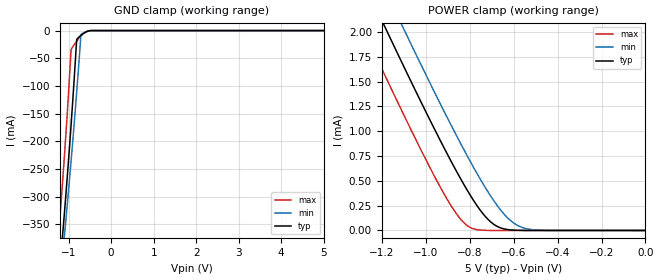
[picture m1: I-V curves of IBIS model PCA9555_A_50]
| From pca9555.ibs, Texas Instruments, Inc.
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[Model]   PCA9555_A_50
Model_type  Input
Vinl=1.35
Vinh=3.85
| variable   typ   min   max
C_comp   3.08pF   1.64pF   7.41pF
[Temperature Range]   40   100   -40
| Ambient temperature   25   85   -40
[Voltage range]   5   4.5   5.5
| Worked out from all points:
|   GND clamp passes 1 mA (typ) near -0.54 V on its own axis
|   POWER clamp passes 1 mA (typ) near -0.96 V on its own axis
[GND Clamp]
| PCA9555_A_50
|   Voltage   I(typ)   I(min)   I(max)
-5.5V     -1.952A    -1.991A    -1.822A
-1.24V    -456.1mA   -482.2mA   -371.1mA
-1.205V   -425.8mA   -455.2mA   -337.1mA
-1.135V   -362.9mA   -399.8mA   -265.2mA
-1.1V     -330.1mA   -371.2mA   -227.1mA
-1.07V    -301.2mA   -346.3mA   -193.2mA
-1.005V   -236.2mA   -290.9mA   -115.2mA
-945mV    -172.6mA   -237.7mA   -36.94mA
-810mV    -16.02mA   -110.1mA   -19.15mA
-710mV    -8.623mA   -7.36mA    -9.218mA
-555mV    -1.256mA   -1.321mA   -672uA
5V        122pA      5.559uA    78.9pA
[POWER Clamp]
| PCA9555_A_50
|   Voltage   I(typ)   I(min)   I(max)
-5.5V     23.22mA    23.56mA    22.79mA
-1.315V   2.658mA    3.034mA    2.172mA
-1.25V    2.35mA     2.727mA    1.863mA
-1.195V   2.092mA    2.469mA    1.605mA
-1.095V   1.628mA    2.005mA    1.141mA
-935mV    911uA      1.281mA    441.2uA
-835mV    496.2uA    849.9uA    97.5uA
-785mV    311.2uA    645.8uA    18.53uA
-715mV    108uA      382.7uA    733.7nA
-610mV    5.103uA    92.47uA    4.595nA
-490mV    68.92nA    4.139uA    120pA
-95.1fV   122pA      284.2pA    92.47pA
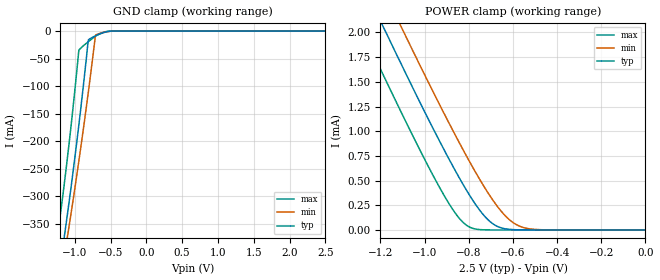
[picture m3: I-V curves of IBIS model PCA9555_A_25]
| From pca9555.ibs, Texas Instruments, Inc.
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[Model]   PCA9555_A_25
Model_type  Input
Vinl=0.69
Vinh=1.89
| variable   typ   min   max
C_comp   1.93pF   1.64pF   3.08pF
[Temperature Range]   40   100   -40
| Ambient temperature   25   85   -40
[Voltage range]   2.5   2.3   2.7
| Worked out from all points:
|   GND clamp passes 1 mA (typ) near -0.55 V on its own axis
|   POWER clamp passes 1 mA (typ) near -0.96 V on its own axis
[GND Clamp]
| PCA9555_A_25
|   Voltage   I(typ)   I(min)   I(max)
-5.5V     -1.952A    -1.991A    -1.822A
-1.245V   -460.3mA   -486mA     -375.9mA
-1.21V    -430.2mA   -459.1mA   -342.1mA
-1.14V    -367.5mA   -403.8mA   -270.6mA
-1.105V   -334.8mA   -375.4mA   -232.7mA
-1.085V   -315.7mA   -358.8mA   -210.3mA
-1.02V    -251.5mA   -303.9mA   -133.8mA
-945mV    -172.6mA   -237.7mA   -36.94mA
-810mV    -16.02mA   -110.1mA   -19.15mA
-710mV    -8.623mA   -7.36mA    -9.218mA
-505mV    -240uA     -374.5uA   -17.49uA
2.5V      65.27pA    853.9pA    39.07pA
[POWER Clamp]
| PCA9555_A_25
|   Voltage   I(typ)   I(min)   I(max)
-5.5V     23.22mA    23.56mA    22.79mA
-1.315V   2.658mA    3.034mA    2.172mA
-1.25V    2.35mA     2.727mA    1.863mA
-1.195V   2.092mA    2.469mA    1.605mA
-1.095V   1.628mA    2.005mA    1.141mA
-935mV    911uA      1.281mA    441.2uA
-835mV    496.2uA    849.9uA    97.5uA
-785mV    311.2uA    645.8uA    18.53uA
-715mV    108uA      382.7uA    733.7nA
-610mV    5.103uA    92.47uA    4.544nA
-490mV    68.86nA    4.139uA    69.34pA
-95.1fV   65.27pA    211.5pA    44.72pA
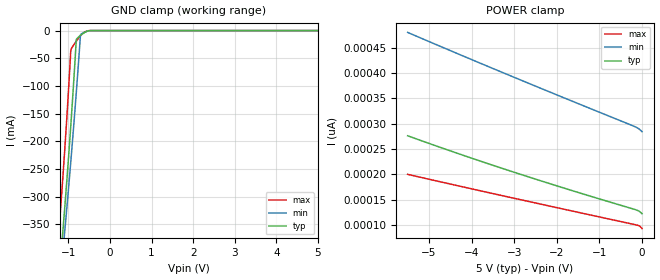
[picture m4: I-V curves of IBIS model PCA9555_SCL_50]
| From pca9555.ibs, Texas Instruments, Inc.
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[Model]   PCA9555_SCL_50
Model_type  Input
Vinl=1.35
Vinh=3.85
| variable   typ   min   max
C_comp   2.89pF   1.56pF   7.17pF
[Temperature Range]   40   100   -40
| Ambient temperature   25   85   -40
[Voltage range]   5   4.5   5.5
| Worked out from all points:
|   GND clamp passes 1 mA (typ) near -0.54 V on its own axis
[GND Clamp]
| PCA9555_SCL_50
|   Voltage   I(typ)   I(min)   I(max)
-5.5V     -1.952A    -1.991A    -1.822A
-1.24V    -456.1mA   -482.2mA   -371.1mA
-1.205V   -425.8mA   -455.2mA   -337.1mA
-1.135V   -362.9mA   -399.8mA   -265.2mA
-1.1V     -330.1mA   -371.2mA   -227.1mA
-1.07V    -301.2mA   -346.3mA   -193.2mA
-1.005V   -236.2mA   -290.9mA   -115.2mA
-945mV    -172.6mA   -237.7mA   -36.94mA
-810mV    -16.02mA   -110.1mA   -19.15mA
-710mV    -8.623mA   -7.36mA    -9.218mA
-555mV    -1.256mA   -1.321mA   -672uA
5V        122pA      305.6pA    79.4pA
[POWER Clamp]
| PCA9555_SCL_50
|   Voltage   I(typ)   I(min)   I(max)
-5.5V     276.1pA    480.5pA    199.8pA
-4.285V   240.1pA    436.9pA    176.6pA
-3.025V   204.6pA    392.5pA    153pA
-1.71V    169.5pA    347pA      128.7pA
-140mV    129.6pA    293pA      99.92pA
-55mV     126.1pA    288.5pA    97.4pA
-95.1fV   122pA      284.2pA    92.47pA
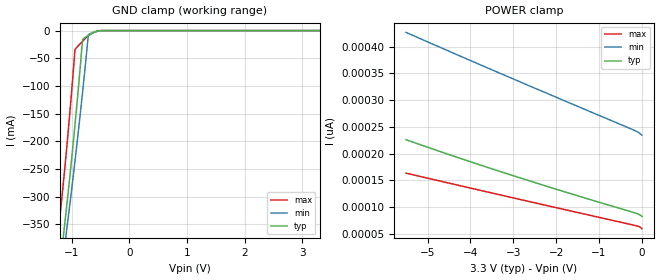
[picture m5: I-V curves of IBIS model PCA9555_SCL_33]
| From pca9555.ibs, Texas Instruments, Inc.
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[Model]   PCA9555_SCL_33
Model_type  Input
Vinl=0.9
Vinh=2.52
| variable   typ   min   max
C_comp   2.12pF   1.54pF   4.92pF
[Temperature Range]   40   100   -40
| Ambient temperature   25   85   -40
[Voltage range]   3.3   3   3.6
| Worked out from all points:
|   GND clamp passes 1 mA (typ) near -0.54 V on its own axis
[GND Clamp]
| PCA9555_SCL_33
|   Voltage   I(typ)   I(min)   I(max)
-5.5V     -1.952A    -1.991A    -1.822A
-1.24V    -456.1mA   -482.2mA   -371.1mA
-1.205V   -425.8mA   -455.2mA   -337.1mA
-1.135V   -362.9mA   -399.8mA   -265.2mA
-1.1V     -330.1mA   -371.2mA   -227.1mA
-1.07V    -301.2mA   -346.3mA   -193.2mA
-1.005V   -236.2mA   -290.9mA   -115.2mA
-945mV    -172.6mA   -237.7mA   -36.94mA
-810mV    -16.02mA   -110.1mA   -19.15mA
-710mV    -8.623mA   -7.36mA    -9.218mA
-505mV    -240uA     -374.5uA   -17.49uA
3.3V      82.96pA    248pA      52.06pA
[POWER Clamp]
| PCA9555_SCL_33
|   Voltage   I(typ)   I(min)   I(max)
-5.5V     226.2pA    426.8pA    163.7pA
-4.255V   191.9pA    383.1pA    140.6pA
-2.945V   157.5pA    337.9pA    116.5pA
-1.625V   124.5pA    292.8pA    92.42pA
-145mV    89pA       242.5pA    65.66pA
-55mV     85.99pA    238.2pA    63.4pA
-95.1fV   82.96pA    234.7pA    59.99pA
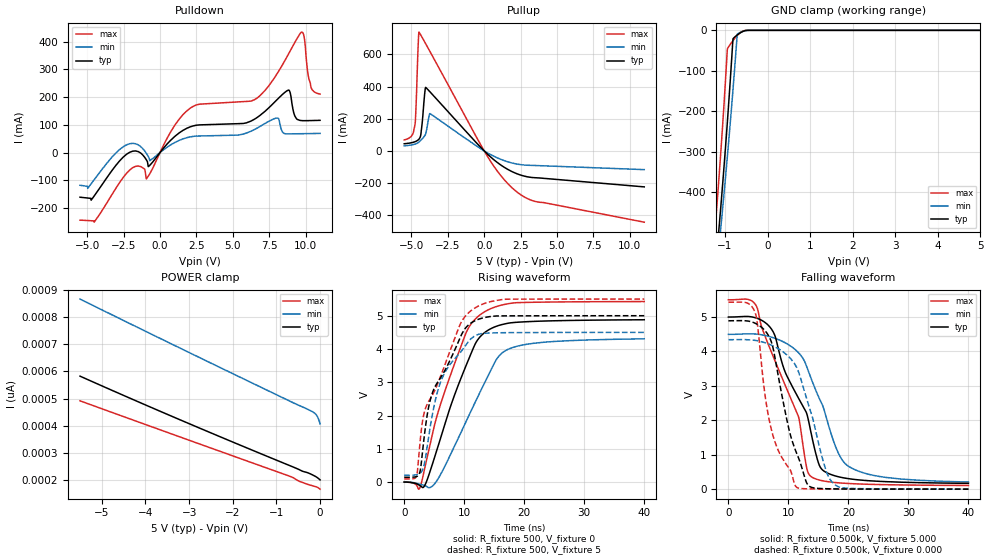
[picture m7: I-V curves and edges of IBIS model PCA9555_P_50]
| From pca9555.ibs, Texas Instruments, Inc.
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[Model]   PCA9555_P_50
Model_type  I/O
Vinl=1.35
Vinh=3.85
Enable   Active-Low
Vref =   5V
Rref =   1k
Cref =   50p
Vmeas =   2.5
| variable   typ   min   max
C_comp   5.26pF   3.57pF   9.96pF
| C_pullup   10.27pF   5.19pF   16.78pF
| C_pulldown   3.97pF   3.22pF   5.97pF
| C_tri-state   5.26pF   3.57pF   9.96pF
[Temperature Range]   40   100   -40
| Ambient temperature   25   85   -40
[Voltage range]   5   4.5   5.5
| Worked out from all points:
|   slope of the pulldown table from 0 to 0.75 V, typ, clamps not added: 16.6 ohm
|   slope of the pullup table from 0 to 0.75 V, typ, clamps not added: 12.2 ohm
|   GND clamp passes 1 mA (typ) near -0.53 V on its own axis
|   rising waveform, R_fixture 500, V_fixture 0: 20-80 % time 5.77ns typ, 6.85ns min, 5.74ns max; typ from 0 V to 4.88 V
|   falling waveform, R_fixture 0.500k, V_fixture 5.000: 20-80 % time 6.04ns typ, 5.41ns min, 6.35ns max; typ from 5 V to 0.169 V
|   rising waveform, R_fixture 500, V_fixture 5: 20-80 % time 5.39ns typ, 4.29ns min, 5.99ns max; typ from 0.145 V to 5 V
|   falling waveform, R_fixture 0.500k, V_fixture 0.000: 20-80 % time 3.86ns typ, 4.17ns min, 3.3ns max; typ from 4.89 V to 0.001 V
[GND Clamp]
| PCA9555_P_50
|   Voltage   I(typ)   I(min)   I(max)
-5.5V     -2.659A    -2.671A    -2.55A
-1.25V    -620.9mA   -649.9mA   -515.2mA
-1.215V   -580.7mA   -614.3mA   -469.4mA
-1.14V    -490.9mA   -535.7mA   -365.6mA
-1.105V   -447.3mA   -497.9mA   -314.2mA
-1.085V   -421.8mA   -476mA     -283.9mA
-1.02V    -335.9mA   -403.1mA   -180.3mA
-945mV    -230.4mA   -315.4mA   -49.25mA
-810mV    -21.17mA   -146.1mA   -25.59mA
-710mV    -11.45mA   -9.703mA   -12.46mA
-575mV    -2.573mA   -2.443mA   -1.831mA
5V        200.9pA    476.3pA    136.3pA
[POWER Clamp]
| PCA9555_P_50
|   Voltage   I(typ)   I(min)   I(max)
-5.5V     582.7pA    866.5pA    491.9pA
-3.195V   421.2pA    684.9pA    358.1pA
-720mV    255.2pA    492.9pA    215.8pA
-620mV    248.5pA    485.2pA    209.3pA
-460mV    237.2pA    473.5pA    194.6pA
-205mV    221.8pA    454.4pA    180.7pA
-125mV    215.3pA    446.6pA    177.1pA
-80mV     211.1pA    439pA      174.8pA
-40mV     206.5pA    426.4pA    171.8pA
-95.1fV   200.9pA    407pA      166.8pA
[Pulldown]
| PCA9555_P_50
|   Voltage   I(typ)   I(min)   I(max)
-5.5V     -161.3mA   -118.2mA   -244mA
-4.53V    -157.1mA   -98.37mA   -251.4mA
-2.09V    700uA      31.71mA    -63.39mA
-810mV    -51.16mA   -14.18mA   -85.28mA
1.86V     87.86mA    53.74mA    151.1mA
6.5V      120.4mA    83.16mA    190.6mA
8.07V     192mA      124.3mA    286.3mA
8.805V    224.8mA    67.3mA     353mA
9.715V    115.2mA    67.82mA    434.4mA
9.91V     114.8mA    67.97mA    415.8mA
10.38V    115.3mA    68.36mA    235.3mA
11V       116.1mA    68.89mA    210.6mA
[Pullup]
| PCA9555_P_50
|   Voltage   I(typ)   I(min)   I(max)
-5.5V     44.69mA    31.56mA    68.44mA
-4.965V   51.88mA    38.04mA    96.98mA
-4.755V   57.61mA    42.62mA    167.1mA
-4.54V    68.59mA    51.23mA    659.1mA
-4.485V   73.46mA    55.14mA    739.4mA
-4.345V   110mA      67.68mA    718.2mA
-4.025V   395.4mA    106.6mA    666.9mA
-3.74V    368.8mA    232.6mA    620.1mA
215mV     -18.98mA   -11.6mA    -32.74mA
2.1V      -136.4mA   -78.84mA   -244.4mA
3.52V     -166.7mA   -90.61mA   -314.5mA
11V       -223.6mA   -116.2mA   -443.2mA
[Ramp]
| PCA9555_P_50
| variable   typ   min   max
dV/dt_r   3.02/5.92E-09   2.68/7.11E-09   3.38/5.86E-09
dV/dt_f   2.91/6.05E-09   2.55/5.43E-09   3.25/6.38E-09
R_load = 500
[Rising Waveform]
| PCA9555_P_50
R_fixture =   500
C_fixture =   0
L_fixture =   0
V_fixture =   0
V_fixture_min = 0
V_fixture_max = 0
|   Time   V(typ)   V(min)   V(max)
0s        1.669nV    3.101nV    1.088nV
2.47ns    -88.81mV   -56.47mV   -210.5mV
3.46ns    -87.73mV   -106.1mV   451.7mV
5.215ns   833.5mV    -17.69mV   1.827V
8.355ns   2.599V     1.072V     3.54V
10.56ns   3.611V     1.916V     4.582V
12.66ns   4.37V      2.713V     5.03V
15.57ns   4.696V     3.739V     5.287V
18.15ns   4.793V     4.048V     5.383V
40ns      4.878V     4.305V     5.425V
[Falling Waveform]
R_fixture = 0.500k
V_fixture = 5.000
V_fixture_min = 4.500
V_fixture_max = 5.500
C_fixture = 0.000
L_fixture = 0.000
|  time   V(typ)   V(min)   V(max)
0s        5V         4.497V     5.5V
4.705ns   4.967V     4.504V     5.302V
7.59ns    4.526V     4.392V     3.802V
11.66ns   2.651V     3.968V     2.117V
13.05ns   2.2V       3.563V     620.6mV
13.76ns   1.649V     3.227V     368.6mV
15.48ns   594.7mV    2.51V      252.3mV
18.09ns   372mV      1.142V     188.7mV
20ns      305.8mV    666.4mV    165.4mV
40ns      169.2mV    207.1mV    107.2mV
[Rising Waveform]
| PCA9555_P_50
R_fixture =   500
C_fixture =   0
L_fixture =   0
V_fixture =   5
V_fixture_min = 4.5
V_fixture_max = 5.5
|   Time   V(typ)   V(min)   V(max)
0s        144.8mV    205.4mV    95.96mV
2.03ns    164.3mV    220.3mV    173.6mV
2.625ns   311.1mV    261.1mV    1.166V
2.99ns    811.4mV    346.6mV    1.759V
4.265ns   2.412V     1.58V      2.48V
6.06ns    3.135V     3.004V     3.181V
9.305ns   4.331V     3.887V     4.733V
11.22ns   4.792V     4.324V     5.163V
16.86ns   4.995V     4.489V     5.494V
40ns      4.999V     4.499V     5.5V
[Falling Waveform]
R_fixture = 0.500k
V_fixture = 0.000
V_fixture_min = 0.000
V_fixture_max = 0.000
C_fixture = 0.000
L_fixture = 0.000
|  time   V(typ)   V(min)   V(max)
0s        4.891V     4.341V     5.43V
4.465ns   4.819V     4.321V     5.123V
6.82ns    4.415V     4.208V     1.994V
8.15ns    3.442V     4.097V     1.19V
10.05ns   1.768V     3.847V     623.5mV
11.37ns   1.046V     3.538V     55.39mV
13.39ns   98.39mV    2.429V     9.881mV
16.28ns   13.79mV    535.9mV    4.686mV
17.83ns   8.967mV    118.8mV    3.599mV
40ns      957uV      1.856mV    497.1uV
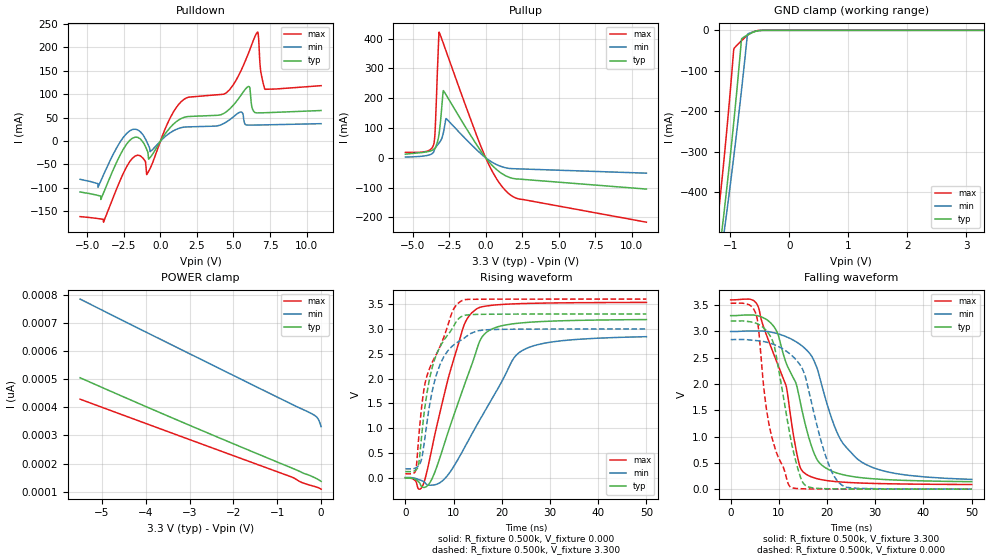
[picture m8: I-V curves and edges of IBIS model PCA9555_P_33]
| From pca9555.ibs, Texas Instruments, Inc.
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[Model]   PCA9555_P_33
Model_type  I/O
Vinl=0.9
Vinh=2.52
Enable   Active-Low
Vref =   3.3V
Rref =   1k
Cref =   50p
Vmeas =   1.65
| variable   typ   min   max
C_comp   4.36pF   3.54pF   7.68pF
| C_pullup   8.79pF   4.63pF   15.14pF
| C_pulldown   3.18pF   2.12pF   3.93pF
| C_tri-state   4.36pF   3.54pF   7.68pF
[Temperature Range]   40   100   -40
| Ambient temperature   25   85   -40
[Voltage range]   3.3   3   3.6
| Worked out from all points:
|   slope of the pulldown table from 0 to 0.495 V, typ, clamps not added: 21.7 ohm
|   slope of the pullup table from 0 to 0.495 V, typ, clamps not added: 17.6 ohm
|   GND clamp passes 1 mA (typ) near -0.53 V on its own axis
|   rising waveform, R_fixture 0.500k, V_fixture 0.000: 20-80 % time 6.77ns typ, 9.64ns min, 5.63ns max; typ from 0 V to 3.19 V
|   falling waveform, R_fixture 0.500k, V_fixture 3.300: 20-80 % time 6.32ns typ, 7.15ns min, 5.91ns max; typ from 3.3 V to 0.142 V
|   rising waveform, R_fixture 0.500k, V_fixture 3.300: 20-80 % time 4.04ns typ, 4ns min, 5.46ns max; typ from 0.127 V to 3.3 V
|   falling waveform, R_fixture 0.500k, V_fixture 0.000: 20-80 % time 3.8ns typ, 5ns min, 3.45ns max; typ from 3.2 V to 0 V
[GND Clamp]
| PCA9555_P_33
|   Voltage   I(typ)   I(min)   I(max)
-5.5V     -2.659A    -2.671A    -2.55A
-1.25V    -620.9mA   -649.9mA   -515.2mA
-1.215V   -580.7mA   -614.3mA   -469.4mA
-1.14V    -490.9mA   -535.7mA   -365.6mA
-1.105V   -447.3mA   -497.9mA   -314.2mA
-1.085V   -421.8mA   -476mA     -283.9mA
-1.02V    -335.9mA   -403.1mA   -180.3mA
-945mV    -230.4mA   -315.4mA   -49.25mA
-810mV    -21.17mA   -146.1mA   -25.59mA
-710mV    -11.45mA   -9.703mA   -12.46mA
-460mV    -14.25uA   -32.32uA   -4.731uA
3.3V      136.5pA    383.9pA    92.9pA
[POWER Clamp]
| PCA9555_P_33
|   Voltage   I(typ)   I(min)   I(max)
-5.5V     505.4pA    785.5pA    429pA
-3.22V    350.6pA    607.7pA    297.7pA
-715mV    186.9pA    414.5pA    154.3pA
-620mV    180.8pA    407.2pA    148.2pA
-450mV    169pA      394.8pA    133.1pA
-210mV    154pA      376.8pA    120.9pA
-130mV    148pA      369.3pA    117.3pA
-80mV     144.1pA    361.4pA    114.9pA
-40mV     140.5pA    349.5pA    112.3pA
-95.1fV   136.5pA    331.1pA    108.6pA
[Pulldown]
| PCA9555_P_33
|   Voltage   I(typ)   I(min)   I(max)
-5.5V     -108.8mA   -81.65mA   -161.4mA
-3.9V     -111.1mA   -72.36mA   -173.3mA
-1.91V    6.229mA    24.76mA    -36.43mA
-1.2V     -1.926mA   13.5mA     -36.3mA
-940mV    -17.78mA   -841.7uA   -71.68mA
1.26V     45.29mA    27.14mA    78.76mA
4.51V     62.52mA    40.64mA    103mA
6.02V     116.6mA    34.12mA    187.2mA
6.64V     60.2mA     34.28mA    232.8mA
6.855V    60.3mA     34.41mA    151.8mA
7.155V    60.56mA    34.61mA    110.6mA
11V       65.25mA    37.16mA    118.3mA
[Pullup]
| PCA9555_P_33
|   Voltage   I(typ)   I(min)   I(max)
-5.5V     12.07mA    2.44mA     18.27mA
-4.035V   20.06mA    7.564mA    21.8mA
-3.555V   28.68mA    20.6mA     45.81mA
-3.465V   33.35mA    31.5mA     89.22mA
-3.19V    81.65mA    50.02mA    421.9mA
-2.9V     225.5mA    83.94mA    383.7mA
-2.71V    211mA      131.6mA    357.5mA
-95mV     6.141mA    3.694mA    10.69mA
700mV     -37.53mA   -21.75mA   -66.95mA
1.495V    -63.29mA   -34.72mA   -116.7mA
2.27V     -71.32mA   -37.15mA   -138.1mA
11V       -105mA     -51.54mA   -216.1mA
[Ramp]
| PCA9555_P_33
| variable   typ   min   max
dV/dt_r   2.03/7.15E-09   1.78/1.02E-08   2.26/5.89E-09
dV/dt_f   1.90/6.33E-09   1.67/7.17E-09   2.12/5.96E-09
R_load = 500
[Rising Waveform]
R_fixture = 0.500k
V_fixture = 0.000
V_fixture_min = 0.000
V_fixture_max = 0.000
C_fixture = 0.000
L_fixture = 0.000
|  time   V(typ)   V(min)   V(max)
0s        1.457nV    9.486mV    934.2pV
3.68ns    -189.5mV   -67.33mV   -137.7mV
5.33ns    -55.59mV   -147.1mV   509.8mV
7.465ns   496.6mV    -76.36mV   1.436V
11.7ns    1.719V     508.3mV    2.932V
14.58ns   2.513V     1.021V     3.388V
17.26ns   2.961V     1.474V     3.466V
22.33ns   3.102V     2.387V     3.502V
24.55ns   3.124V     2.58V      3.51V
50ns      3.187V     2.843V     3.533V
[Falling Waveform]
R_fixture = 0.500k
V_fixture = 3.300
V_fixture_min = 3.000
V_fixture_max = 3.600
C_fixture = 0.000
L_fixture = 0.000
|  time   V(typ)   V(min)   V(max)
0s        3.3V       2.998V     3.6V
5.685ns   3.296V     3.007V     3.477V
9.67ns    2.979V     2.958V     2.395V
11.52ns   2.397V     2.899V     1.958V
13.85ns   1.914V     2.787V     623.3mV
15.33ns   1.288V     2.683V     304.8mV
18.52ns   489.9mV    2.111V     186.6mV
22.28ns   300.3mV    1.037V     140.7mV
26.51ns   224.7mV    558.4mV    118.5mV
50ns      142.4mV    185.5mV    88.51mV
[Rising Waveform]
R_fixture = 0.500k
V_fixture = 3.300
V_fixture_min = 3.000
V_fixture_max = 3.600
C_fixture = 0.000
L_fixture = 0.000
|  time   V(typ)   V(min)   V(max)
0s        126.8mV    183.4mV    82.7mV
2.06ns    149.9mV    196.9mV    127mV
2.6ns     216.1mV    230.5mV    609.6mV
3.29ns    751.7mV    355.8mV    1.35V
3.915ns   1.322V     707.5mV    1.816V
5.67ns    2.258V     1.787V     2.345V
7.945ns   2.765V     2.431V     2.825V
11.1ns    3.209V     2.748V     3.528V
16.73ns   3.294V     2.981V     3.597V
50ns      3.3V       2.999V     3.6V
[Falling Waveform]
R_fixture = 0.500k
V_fixture = 0.000
V_fixture_min = 0.000
V_fixture_max = 0.000
C_fixture = 0.000
L_fixture = 0.000
|  time   V(typ)   V(min)   V(max)
0s        3.197V     2.844V     3.536V
5.26ns    3.156V     2.826V     3.325V
7.08ns    3.046V     2.803V     1.765V
8.02ns    2.939V     2.781V     1.203V
9.18ns    2.672V     2.743V     786.7mV
12.38ns   992.6mV    2.566V     44.12mV
15.3ns    88.47mV    2.194V     6.862mV
19.64ns   9.347mV    648.3mV    2.802mV
22.99ns   4.719mV    82.58mV    1.826mV
50ns      496uV      1.201mV    227.2uV
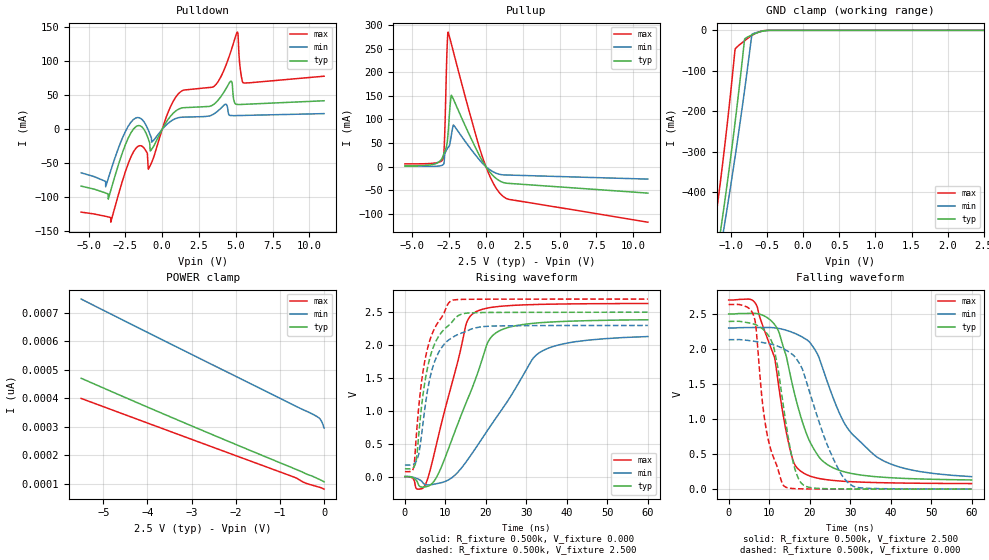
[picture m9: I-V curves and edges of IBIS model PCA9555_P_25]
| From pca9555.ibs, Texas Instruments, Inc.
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[Model]   PCA9555_P_25
Model_type  I/O
Vinl=0.69
Vinh=1.89
Enable   Active-Low
Vref =   2.5V
Rref =   1k
Cref =   50p
Vmeas =   1.25
| variable   typ   min   max
C_comp   3.89pF   3.28pF   5.37pF
| C_pullup   7.69pF   4.25pF   13.66pF
| C_pulldown   2.92pF   1.84pF   3.90pF
| C_tri-state   3.89pF   3.28pF   5.37pF
[Temperature Range]   40   100   -40
| Ambient temperature   25   85   -40
[Voltage range]   2.5   2.3   2.7
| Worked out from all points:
|   slope of the pulldown table from 0 to 0.375 V, typ, clamps not added: 27.3 ohm
|   slope of the pullup table from 0 to 0.375 V, typ, clamps not added: 24.6 ohm
|   GND clamp passes 1 mA (typ) near -0.53 V on its own axis
|   rising waveform, R_fixture 0.500k, V_fixture 0.000: 20-80 % time 8.64ns typ, 13.3ns min, 6.46ns max; typ from 0 V to 2.38 V
|   falling waveform, R_fixture 0.500k, V_fixture 2.500: 20-80 % time 7.2ns typ, 11.5ns min, 5.6ns max; typ from 2.5 V to 0.131 V
|   rising waveform, R_fixture 0.500k, V_fixture 2.500: 20-80 % time 4.04ns typ, 4.18ns min, 3.95ns max; typ from 0.119 V to 2.5 V
|   falling waveform, R_fixture 0.500k, V_fixture 0.000: 20-80 % time 4.01ns typ, 7.67ns min, 3.57ns max; typ from 2.39 V to 0 V
[GND Clamp]
| PCA9555_P_25
|   Voltage   I(typ)   I(min)   I(max)
-5.5V     -2.659A    -2.671A    -2.55A
-1.25V    -620.9mA   -649.9mA   -515.2mA
-1.215V   -580.7mA   -614.3mA   -469.4mA
-1.14V    -490.9mA   -535.7mA   -365.6mA
-1.105V   -447.3mA   -497.9mA   -314.2mA
-1.085V   -421.8mA   -476mA     -283.9mA
-1.02V    -335.9mA   -403.1mA   -180.3mA
-945mV    -230.4mA   -315.4mA   -49.25mA
-810mV    -21.17mA   -146.1mA   -25.59mA
-710mV    -11.45mA   -9.703mA   -12.46mA
-505mV    -366uA     -518.4uA   -66.4uA
2.5V      107pA      339.4pA    70.63pA
[POWER Clamp]
| PCA9555_P_25
|   Voltage   I(typ)   I(min)   I(max)
-5.5V     470.3pA    748.2pA    399.6pA
-3.22V    317.7pA    571.1pA    268.6pA
-720mV    156.1pA    378.4pA    125.8pA
-620mV    149.7pA    370.7pA    119.5pA
-445mV    137.7pA    358pA      104.1pA
-210mV    122.8pA    340.2pA    92.53pA
-130mV    117.1pA    332.7pA    89.02pA
-80mV     113.5pA    325pA      86.67pA
-40mV     110.3pA    313.4pA    84.34pA
-95.1fV   107pA      295.5pA    81.18pA
[Pulldown]
| PCA9555_P_25
|   Voltage   I(typ)   I(min)   I(max)
-5.5V     -83.52mA   -63.92mA   -121.8mA
-3.835V   -93.61mA   -84.49mA   -128mA
-3.49V    -89.78mA   -60.55mA   -136.6mA
-1.775V   4.147mA    16.88mA    -27.64mA
-1.1V     -5.415mA   6.314mA    -31.68mA
-935mV    -14.35mA   -1.386mA   -58.57mA
885mV     26.39mA    15.61mA    46.22mA
3.625V    38.95mA    24.32mA    65.29mA
4.68V     71mA       20.37mA    115.6mA
5.105V    36.75mA    20.3mA     143.1mA
5.485V    36.78mA    20.49mA    68.68mA
11V       42.1mA     23.18mA    78.24mA
[Pullup]
| PCA9555_P_25
|   Voltage   I(typ)   I(min)   I(max)
-5.5V     1.58mA     817.9uA    5.893mA
-3.53V    5.067mA    807.9uA    7.411mA
-2.905V   23.01mA    4.267mA    17.45mA
-2.855V   27.07mA    6.471mA    27.03mA
-2.805V   31.06mA    22.7mA     61.94mA
-2.65V    47.02mA    36.78mA    239.5mA
-2.57V    70.66mA    40.55mA    285.1mA
-2.34V    151.3mA    68.02mA    259.2mA
-2.2V     142.4mA    87.97mA    242.4mA
-265mV    13.44mA    8.084mA    23.32mA
1.08V     -32.41mA   -17.09mA   -60.59mA
11V       -56.04mA   -26.38mA   -117.6mA
[Ramp]
| PCA9555_P_25
| variable   typ   min   max
dV/dt_r   1.53/9.25E-09   1.33/1.42E-08   1.69/6.91E-09
dV/dt_f   1.43/7.22E-09   1.24/1.15E-08   1.58/5.66E-09
R_load = 500
[Rising Waveform]
R_fixture = 0.500k
V_fixture = 0.000
V_fixture_min = 0.000
V_fixture_max = 0.000
C_fixture = 0.000
L_fixture = 0.000
|  time   V(typ)   V(min)   V(max)
0s        1.361nV    2.549mV    856.6pV
1.94ns    -14.76mV   -7.089mV   -24.52mV
3.01ns    -73.14mV   -29.53mV   -189.1mV
5.225ns   -152.1mV   -122.6mV   -96.71mV
8.325ns   52.81mV    -100.3mV   632.3mV
15.06ns   1.115V     220.3mV    2.308V
16.95ns   1.402V     385.7mV    2.485V
21.75ns   2.151V     825.9mV    2.577V
33.25ns   2.34V      1.886V     2.619V
60ns      2.385V     2.13V      2.633V
[Falling Waveform]
R_fixture = 0.500k
V_fixture = 2.500
V_fixture_min = 2.300
V_fixture_max = 2.700
C_fixture = 0.000
L_fixture = 0.000
|  time   V(typ)   V(min)   V(max)
0s        2.5V       2.3V       2.7V
6.95ns    2.506V     2.307V     2.616V
11.28ns   2.354V     2.303V     1.889V
12.36ns   2.25V      2.294V     1.471V
15.37ns   1.588V     2.246V     518.9mV
17.8ns    1.037V     2.183V     257.1mV
23.52ns   387.4mV    1.674V     140.7mV
28.84ns   243.4mV    916.6mV    111.3mV
35.94ns   180.4mV    488.8mV    94.99mV
60ns      131.5mV    178.7mV    79.81mV
[Rising Waveform]
R_fixture = 0.500k
V_fixture = 2.500
V_fixture_min = 2.300
V_fixture_max = 2.700
C_fixture = 0.000
L_fixture = 0.000
|  time   V(typ)   V(min)   V(max)
0s        118.9mV    176.1mV    76.15mV
2.215ns   148.2mV    191.6mV    149.7mV
2.86ns    275.9mV    242.1mV    655.8mV
3.875ns   935.3mV    525.2mV    1.327V
5.74ns    1.701V     1.364V     1.986V
7.96ns    2.095V     1.842V     2.325V
11.27ns   2.325V     2.098V     2.667V
14.02ns   2.472V     2.184V     2.695V
20.14ns   2.496V     2.285V     2.698V
60ns      2.5V       2.299V     2.7V
[Falling Waveform]
R_fixture = 0.500k
V_fixture = 0.000
V_fixture_min = 0.000
V_fixture_max = 0.000
C_fixture = 0.000
L_fixture = 0.000
|  time   V(typ)   V(min)   V(max)
0s        2.394V     2.133V     2.635V
6.28ns    2.354V     2.111V     2.458V
9.35ns    2.229V     2.082V     827.8mV
11.24ns   2V         2.057V     429.6mV
13.81ns   1.068V     1.995V     38.1mV
15.96ns   375.2mV    1.912V     9.067mV
17.93ns   87.52mV    1.747V     4.848mV
24.54ns   6.22mV     605.4mV    1.616mV
29.96ns   2.693mV    70.57mV    945.3uV
60ns      311.3uV    1.038mV    121.2uV
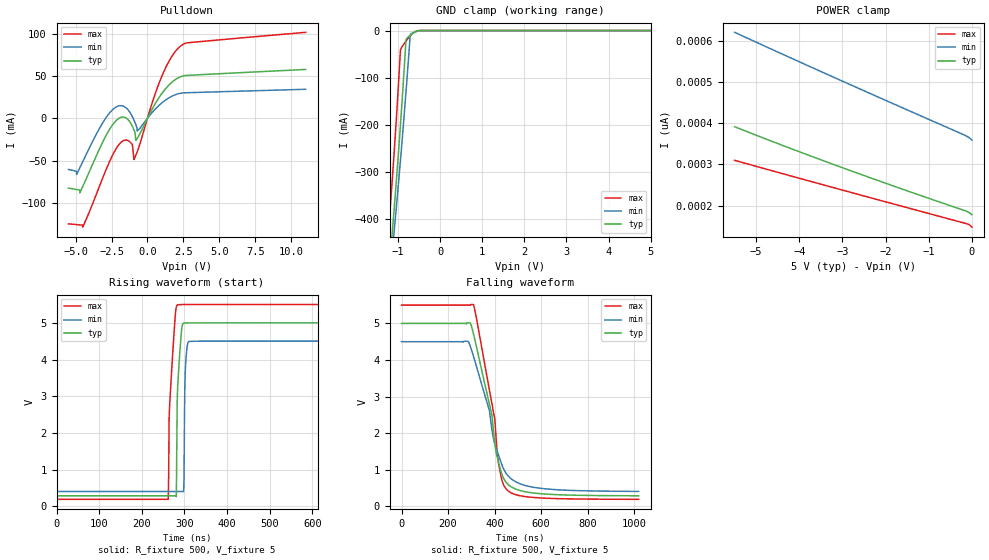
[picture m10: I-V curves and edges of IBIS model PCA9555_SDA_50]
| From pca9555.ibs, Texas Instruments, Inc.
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[Model]   PCA9555_SDA_50
Model_type  I/O_open_drain
Vinl=1.35
Vinh=3.85
Enable   Active-Low
Vref =   5V
Rref =   1k
Cref =   50p
Vmeas =   2.5
| variable   typ   min   max
C_comp   3.64pF   1.88pF   8.24pF
| C_pulldown   1.78pF   0.61pF   3.09pF
| C_tri-state   3.64pF   1.88pF   8.24pF
[Temperature Range]   40   100   -40
| Ambient temperature   25   85   -40
[Voltage range]   5   4.5   5.5
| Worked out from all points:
|   slope of the pulldown table from 0 to 0.75 V, typ, clamps not added: 32.5 ohm
|   GND clamp passes 1 mA (typ) near -0.53 V on its own axis
|   rising waveform, R_fixture 500, V_fixture 5: 20-80 % time 6.62ns typ, 2.65ns min, 10.7ns max; typ from 0.282 V to 5 V
|   falling waveform, R_fixture 500, V_fixture 5: 20-80 % time 83ns typ, 97.6ns min, 73.1ns max; typ from 5 V to 0.285 V
[GND Clamp]
| PCA9555_SDA_50
|   Voltage   I(typ)   I(min)   I(max)
-5.5V     -2.312A    -2.337A    -2.193A
-1.245V   -538.5mA   -565.9mA   -443.1mA
-1.21V    -503.2mA   -534.5mA   -403.1mA
-1.14V    -429.8mA   -470.1mA   -318.6mA
-1.12V    -408.1mA   -451.2mA   -293.3mA
-1.105V   -391.6mA   -437mA     -273.9mA
-1.085V   -369.2mA   -417.7mA   -247.5mA
-940mV    -195.3mA   -271.5mA   -39.92mA
-810mV    -18.61mA   -128.2mA   -22.4mA
-710mV    -10.04mA   -8.533mA   -10.85mA
-605mV    -3.588mA   -3.153mA   -2.905mA
5V        177.6pA    386.7pA    129.5pA
[POWER Clamp]
| PCA9555_SDA_50
|   Voltage   I(typ)   I(min)   I(max)
-5.5V     391.8pA    621.5pA    310.1pA
-4.285V   342.3pA    563.3pA    274.7pA
-3.025V   293pA      503.8pA    238.4pA
-1.675V   242.3pA    440.9pA    199.9pA
-140mV    186.8pA    369.8pA    156.4pA
-55mV     182.4pA    364.3pA    153pA
-95.1fV   177.6pA    359.3pA    147.5pA
[Pulldown]
| PCA9555_SDA_50
|   Voltage   I(typ)   I(min)   I(max)
-5.5V     -82.5mA    -60.5mA    -124.8mA
-4.93V    -84.17mA   -66.36mA   -125.6mA
-4.51V    -80.98mA   -51.62mA   -128.6mA
-2.905V   -21.24mA   122uA      -61.78mA
-1.86V    978uA      14.89mA    -28.83mA
-1.05V    -9.62mA    1.862mA    -31.04mA
-940mV    -13.81mA   -2.131mA   -48.82mA
-810mV    -26.15mA   -7.466mA   -43.65mA
-705mV    -23.57mA   -14.99mA   -39.23mA
950mV     28.07mA    17.41mA    47.58mA
2.295V    48.95mA    29.48mA    85.2mA
11V       57.63mA    34.2mA     101.5mA
[Ramp]
| PCA9555_SDA_50
| variable   typ   min   max
dV/dt_r   2.86/6.46E-09   2.46/2.64E-09   3.24/1.08E-08
dV/dt_f   2.84/8.33E-08   2.47/9.80E-08   3.20/7.34E-08
R_load = 500
[Rising Waveform]
| PCA9555_SDA_50
R_fixture =   500
C_fixture =   0
L_fixture =   0
V_fixture =   5
V_fixture_min = 4.5
V_fixture_max = 5.5
|   Time   V(typ)   V(min)   V(max)
0s        282.3mV    400mV      187mV
262ns     282.3mV    400mV      187mV
265ns     282.3mV    400mV      2.68V
281ns     259.8mV    400mV      5.437V
283ns     2.87V      400mV      5.484V
284ns     3.232V     400mV      5.491V
298ns     4.99V      395mV      5.499V
302ns     4.996V     3.703V     5.499V
310ns     4.998V     4.486V     5.5V
1.019us   5V         4.5V       5.5V
[Falling Waveform]
| PCA9555_SDA_50
R_fixture =   500
C_fixture =   0
L_fixture =   0
V_fixture =   5
V_fixture_min = 4.5
V_fixture_max = 5.5
|   Time   V(typ)   V(min)   V(max)
0s        5V         4.5V       5.5V
285ns     5.015V     4.511V     5.5V
309ns     4.716V     4.104V     5.511V
378ns     2.779V     2.605V     3.16V
389ns     2.477V     2.075V     2.78V
401ns     1.701V     1.697V     2.365V
418ns     1.169V     1.373V     1.114V
458ns     596mV      829.7mV    419.6mV
599ns     341.6mV    488.6mV    225.8mV
1.019us   285mV      404.4mV    188.7mV
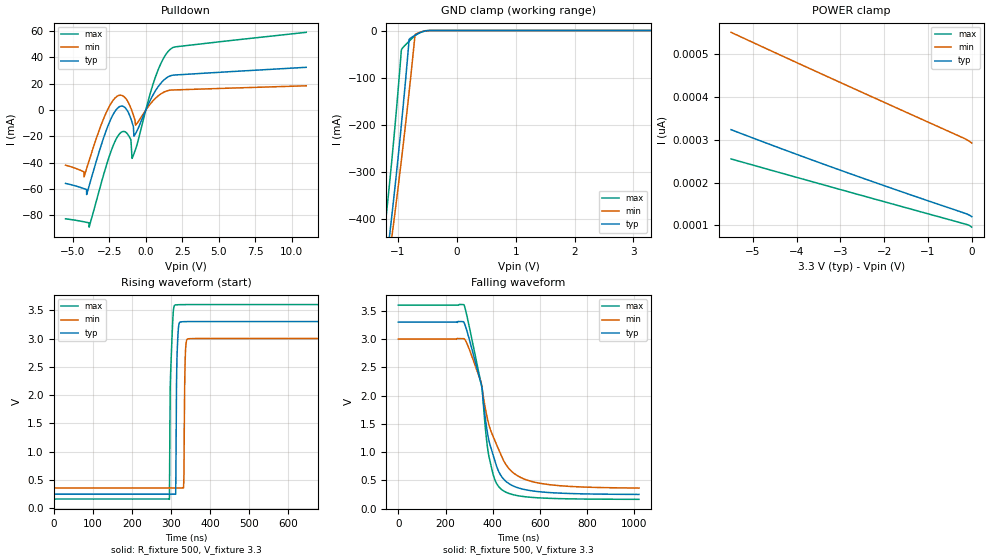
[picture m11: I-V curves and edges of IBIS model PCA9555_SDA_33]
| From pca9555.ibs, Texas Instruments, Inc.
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[Model]   PCA9555_SDA_33
Model_type  I/O_open_drain
Vinl=0.9
Vinh=2.52
Enable   Active-Low
Vref =   3.3V
Rref =   1k
Cref =   50p
Vmeas =   1.65
| variable   typ   min   max
C_comp   2.83pF   1.92pF   6.05pF
| C_pulldown   1.24pF   0.01pF   2.17pF
| C_tri-state   2.83pF   1.92pF   6.05pF
[Temperature Range]   40   100   -40
| Ambient temperature   25   85   -40
[Voltage range]   3.3   3   3.6
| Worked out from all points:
|   slope of the pulldown table from 0 to 0.495 V, typ, clamps not added: 43.2 ohm
|   GND clamp passes 1 mA (typ) near -0.54 V on its own axis
|   rising waveform, R_fixture 500, V_fixture 3.3: 20-80 % time 2.73ns typ, 2.35ns min, 5.36ns max; typ from 0.247 V to 3.3 V
|   falling waveform, R_fixture 500, V_fixture 3.3: 20-80 % time 87.8ns typ, 111ns min, 71.9ns max; typ from 3.3 V to 0.249 V
[GND Clamp]
| PCA9555_SDA_33
|   Voltage   I(typ)   I(min)   I(max)
-5.5V     -2.312A    -2.337A    -2.193A
-1.25V    -543.5mA   -570.3mA   -448.7mA
-1.215V   -508.3mA   -539.1mA   -408.9mA
-1.14V    -429.8mA   -470.1mA   -318.6mA
-1.105V   -391.6mA   -437mA     -273.9mA
-1.085V   -369.2mA   -417.7mA   -247.5mA
-1.02V    -294.1mA   -353.7mA   -157.3mA
-945mV    -201.7mA   -276.7mA   -43.16mA
-810mV    -18.61mA   -128.2mA   -22.4mA
-710mV    -10.04mA   -8.533mA   -10.85mA
-460mV    -11.81uA   -26.04uA   -3.816uA
3.3V      120.4pA    308.7pA    85.1pA
[POWER Clamp]
| PCA9555_SDA_33
|   Voltage   I(typ)   I(min)   I(max)
-5.5V     323.1pA    549.8pA    254.9pA
-4.35V    278.7pA    495.6pA    221.9pA
-2.99V    228.2pA    432.4pA    183.3pA
-1.65V    180.2pA    370.6pA    145.4pA
-145mV    128pA      301.4pA    103.2pA
-55mV     124pA      296pA      100pA
-95.1fV   120.4pA    291.9pA    96.03pA
[Pulldown]
| PCA9555_SDA_33
|   Voltage   I(typ)   I(min)   I(max)
-5.5V     -55.66mA   -41.8mA    -82.53mA
-4.235V   -59.62mA   -50.82mA   -84.79mA
-3.885V   -57.6mA    -38.33mA   -88.86mA
-2.64V    -13.31mA   -190uA     -39.79mA
-1.735V   2.908mA    11.31mA    -17.29mA
-1.025V   -6.474mA   1.564mA    -22.36mA
-940mV    -9.319mA   -953.4uA   -36.66mA
-800mV    -19.64mA   -5.587mA   -32.75mA
-700mV    -17.83mA   -11.37mA   -29.7mA
660mV     14.6mA     8.915mA    25.01mA
1.72V     26.15mA    15.19mA    46.49mA
11V       32.48mA    18.44mA    59.03mA
[Ramp]
| PCA9555_SDA_33
| variable   typ   min   max
dV/dt_r   1.84/2.56E-09   1.59/2.25E-09   2.08/5.20E-09
dV/dt_f   1.84/8.81E-08   1.59/1.11E-07   2.07/7.23E-08
R_load = 500
[Rising Waveform]
| PCA9555_SDA_33
R_fixture =   500
C_fixture =   0
L_fixture =   0
V_fixture =   3.3
V_fixture_min = 3
V_fixture_max = 3.6
|   Time   V(typ)   V(min)   V(max)
0s        247.1mV    356.9mV    161.2mV
296ns     247.1mV    356.9mV    155.8mV
298ns     247.1mV    356.9mV    2.146V
310ns     247.1mV    356.9mV    3.591V
315ns     2.596V     356.9mV    3.596V
323ns     3.29V      356.9mV    3.599V
332ns     3.298V     357.3mV    3.6V
336ns     3.299V     2.585V     3.6V
342ns     3.299V     2.99V      3.6V
1.019us   3.3V       3V         3.6V
[Falling Waveform]
| PCA9555_SDA_33
R_fixture =   500
C_fixture =   0
L_fixture =   0
V_fixture =   3.3
V_fixture_min = 3
V_fixture_max = 3.6
|   Time   V(typ)   V(min)   V(max)
0s        3.3V       3V         3.6V
278ns     3.294V     3.006V     3.605V
355ns     2.107V     2.115V     2.123V
371ns     1.518V     1.718V     1.322V
384ns     1.197V     1.477V     916.3mV
408ns     856.9mV    1.21V      517.6mV
438ns     561.7mV    919.8mV    333.9mV
489ns     394.2mV    623.7mV    241.4mV
577ns     306.3mV    465.7mV    193.4mV
1.019us   249.4mV    361.7mV    162.3mV
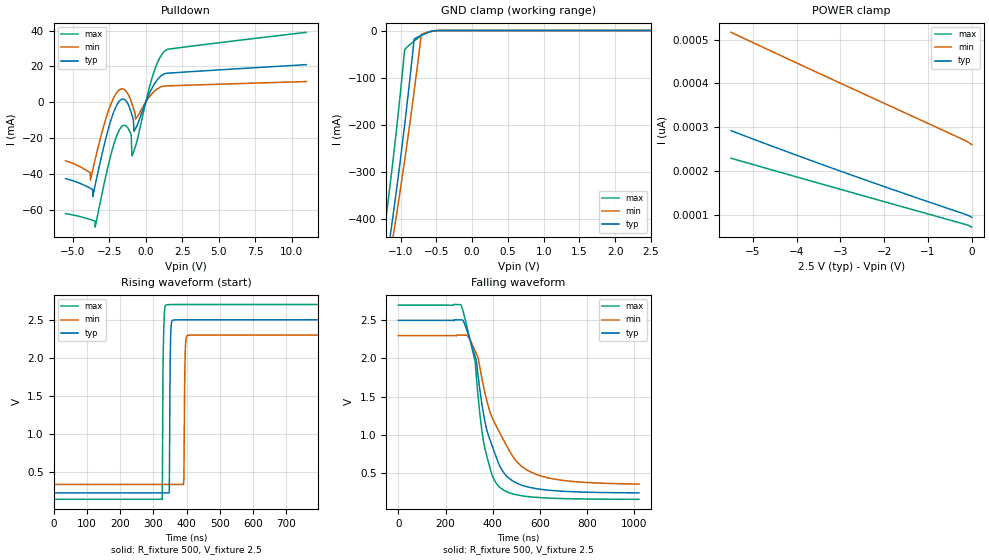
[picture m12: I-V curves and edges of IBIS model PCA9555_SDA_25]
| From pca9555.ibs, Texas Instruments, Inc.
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[Model]   PCA9555_SDA_25
Model_type  I/O_open_drain
Vinl=0.69
Vinh=1.89
Enable   Active-Low
Vref =   2.5V
Rref =   1k
Cref =   50p
Vmeas =   1.25
| variable   typ   min   max
C_comp   2.39pF   1.90pF   3.78pF
| C_pulldown   1.07pF   0.04pF   2.15pF
| C_tri-state   2.39pF   1.90pF   3.78pF
[Temperature Range]   40   100   -40
| Ambient temperature   25   85   -40
[Voltage range]   2.5   2.3   2.7
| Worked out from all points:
|   slope of the pulldown table from 0 to 0.375 V, typ, clamps not added: 53.7 ohm
|   GND clamp passes 1 mA (typ) near -0.54 V on its own axis
|   rising waveform, R_fixture 500, V_fixture 2.5: 20-80 % time 2.25ns typ, 2.56ns min, 2.77ns max; typ from 0.232 V to 2.5 V
|   falling waveform, R_fixture 500, V_fixture 2.5: 20-80 % time 93.8ns typ, 136ns min, 71.9ns max; typ from 2.5 V to 0.234 V
[GND Clamp]
| PCA9555_SDA_25
|   Voltage   I(typ)   I(min)   I(max)
-5.5V     -2.312A    -2.337A    -2.193A
-1.25V    -543.5mA   -570.3mA   -448.7mA
-1.215V   -508.3mA   -539.1mA   -408.9mA
-1.14V    -429.8mA   -470.1mA   -318.6mA
-1.105V   -391.6mA   -437mA     -273.9mA
-1.085V   -369.2mA   -417.7mA   -247.5mA
-1.02V    -294.1mA   -353.7mA   -157.3mA
-945mV    -201.7mA   -276.7mA   -43.16mA
-810mV    -18.61mA   -128.2mA   -22.4mA
-710mV    -10.04mA   -8.533mA   -10.85mA
-505mV    -303.2uA   -446.3uA   -42.12uA
2.5V      94.18pA    271.9pA    64.3pA
[POWER Clamp]
| PCA9555_SDA_25
|   Voltage   I(typ)   I(min)   I(max)
-5.5V     292.1pA    516.7pA    229.1pA
-3.295V   210.3pA    414.1pA    166.5pA
-1.79V    157.1pA    344.9pA    124.1pA
-240mV    104.3pA    273.7pA    80.67pA
-70mV     98.01pA    265pA      75.64pA
-95.1fV   94.18pA    260.2pA    71.75pA
[Pulldown]
| PCA9555_SDA_25
|   Voltage   I(typ)   I(min)   I(max)
-5.5V     -42.74mA   -32.74mA   -62.3mA
-3.8V     -48.13mA   -43.54mA   -65.6mA
-3.47V    -46.4mA    -31.98mA   -69.85mA
-1.905V   -515uA     6.183mA    -17.08mA
-1.205V   -1.262mA   4.251mA    -14.77mA
-1.005V   -5.602mA   467.1uA    -18.2mA
-935mV    -7.531mA   -1.172mA   -29.93mA
-800mV    -16.18mA   -4.65mA    -26.95mA
-700mV    -14.75mA   -9.44mA    -24.52mA
475mV     8.521mA    5.134mA    14.72mA
1.345V    15.98mA    9.024mA    28.85mA
11V       20.93mA    11.5mA     38.99mA
[Ramp]
| PCA9555_SDA_25
| variable   typ   min   max
dV/dt_r   1.36/2.16E-09   1.17/2.46E-09   1.54/2.62E-09
dV/dt_f   1.36/9.42E-08   1.17/1.36E-07   1.54/7.22E-08
R_load = 500
[Rising Waveform]
| PCA9555_SDA_25
R_fixture =   500
C_fixture =   0
L_fixture =   0
V_fixture =   2.5
V_fixture_min = 2.3
V_fixture_max = 2.7
|   Time   V(typ)   V(min)   V(max)
0s        231.7mV    342.8mV    148.5mV
327ns     231.7mV    342.8mV    148mV
330ns     231.7mV    342.8mV    2.107V
338ns     231.7mV    342.8mV    2.692V
348ns     233mV      342.8mV    2.698V
351ns     2.024V     342.8mV    2.699V
357ns     2.49V      342.8mV    2.699V
391ns     2.5V       343mV      2.7V
402ns     2.5V       2.293V     2.7V
1.019us   2.5V       2.3V       2.7V
[Falling Waveform]
| PCA9555_SDA_25
R_fixture =   500
C_fixture =   0
L_fixture =   0
V_fixture =   2.5
V_fixture_min = 2.3
V_fixture_max = 2.7
|   Time   V(typ)   V(min)   V(max)
0s        2.5V       2.3V       2.7V
266ns     2.506V     2.306V     2.698V
325ns     2.026V     2.102V     1.963V
347ns     1.551V     1.853V     1.226V
366ns     1.184V     1.558V     824.7mV
399ns     838.3mV    1.211V     454.7mV
434ns     561.4mV    995.9mV    296.2mV
504ns     358.5mV    636.8mV    206.9mV
590ns     286.8mV    470.3mV    174.2mV
1.019us   234.3mV    349.6mV    149.6mV
